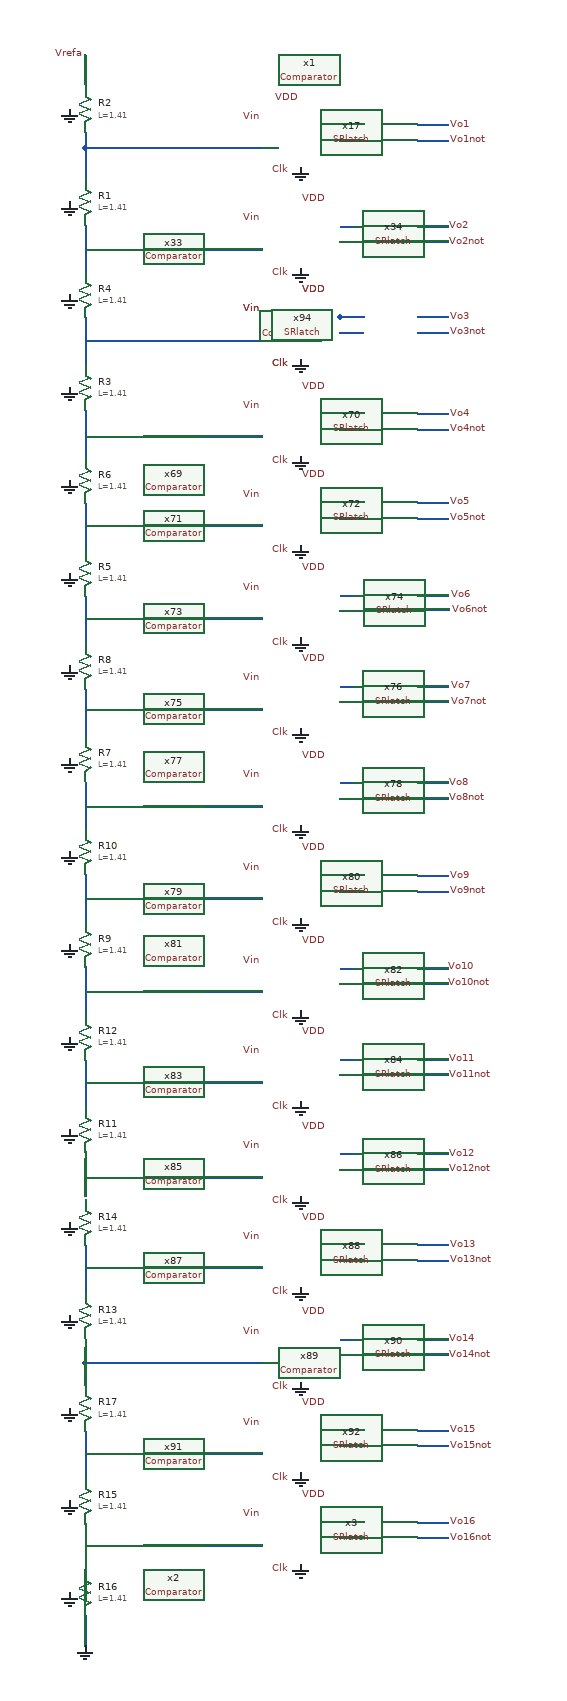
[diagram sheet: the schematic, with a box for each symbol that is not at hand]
v {xschem version=3.4.4 file_version=1.2
}
G {}
K {}
V {}
S {}
E {}
N -1900 -3260 -1670 -3260 {
lab=#net1}
N -1470 -3290 -1430 -3290 {
lab=Vo1}
N -1470 -3270 -1430 -3270 {
lab=Vo1not}
N -1900 -3280 -1900 -3260 {
lab=#net1}
N -1900 -3260 -1900 -3250 {
lab=#net1}
N -1900 -3250 -1900 -3220 {
lab=#net1}
N -1900 -3040 -1900 -3020 {
lab=#net2}
N -1900 -3020 -1900 -3010 {
lab=#net2}
N -1900 -3010 -1900 -2980 {
lab=#net2}
N -1900 -2800 -1900 -2780 {
lab=#net3}
N -1900 -2780 -1900 -2770 {
lab=#net3}
N -1900 -2770 -1900 -2740 {
lab=#net3}
N -1900 -2560 -1900 -2540 {
lab=#net4}
N -1900 -2540 -1900 -2530 {
lab=#net4}
N -1900 -2530 -1900 -2500 {
lab=#net4}
N -1900 -2320 -1900 -2300 {
lab=#net5}
N -1900 -2300 -1900 -2290 {
lab=#net5}
N -1900 -2290 -1900 -2260 {
lab=#net5}
N -1900 -2080 -1900 -2060 {
lab=#net6}
N -1900 -2060 -1900 -2050 {
lab=#net6}
N -1900 -2050 -1900 -2020 {
lab=#net6}
N -1900 -1840 -1900 -1820 {
lab=#net7}
N -1900 -1820 -1900 -1810 {
lab=#net7}
N -1900 -1810 -1900 -1780 {
lab=#net7}
N -1900 -1600 -1900 -1580 {
lab=#net8}
N -1900 -1580 -1900 -1570 {
lab=#net8}
N -1900 -1570 -1900 -1540 {
lab=#net8}
N -1900 -3160 -1900 -3100 {
lab=#net9}
N -1900 -2920 -1900 -2850 {
lab=#net10}
N -1900 -2680 -1900 -2620 {
lab=#net11}
N -1900 -3380 -1900 -3342.5 {
lab=#net12}
N -1570 -3290 -1552.5 -3290 {
lab=#net13}
N -1570 -3290 -1538.75 -3290 {
lab=#net13}
N -1571.25 -3270 -1540 -3270 {
lab=#net14}
N -1900 -3128.75 -1670 -3128.75 {
lab=#net9}
N -1470 -3158.75 -1430 -3158.75 {
lab=Vo2}
N -1470 -3138.75 -1430 -3138.75 {
lab=Vo2not}
N -1570 -3158.75 -1552.5 -3158.75 {
lab=#net15}
N -1570 -3158.75 -1538.75 -3158.75 {
lab=#net15}
N -1571.25 -3138.75 -1540 -3138.75 {
lab=#net16}
N -1900 -3011.25 -1670 -3011.25 {
lab=#net2}
N -1470 -3041.25 -1430 -3041.25 {
lab=Vo3}
N -1470 -3021.25 -1430 -3021.25 {
lab=Vo3not}
N -1570 -3041.25 -1552.5 -3041.25 {
lab=#net17}
N -1570 -3041.25 -1538.75 -3041.25 {
lab=#net17}
N -1571.25 -3021.25 -1540 -3021.25 {
lab=#net18}
N -1900 -2886.25 -1670 -2886.25 {
lab=#net10}
N -1470 -2916.25 -1430 -2916.25 {
lab=Vo4}
N -1470 -2896.25 -1430 -2896.25 {
lab=Vo4not}
N -1570 -2916.25 -1552.5 -2916.25 {
lab=#net19}
N -1570 -2916.25 -1538.75 -2916.25 {
lab=#net19}
N -1571.25 -2896.25 -1540 -2896.25 {
lab=#net20}
N -1900 -2771.25 -1670 -2771.25 {
lab=#net3}
N -1470 -2801.25 -1430 -2801.25 {
lab=Vo5}
N -1470 -2781.25 -1430 -2781.25 {
lab=Vo5not}
N -1570 -2801.25 -1552.5 -2801.25 {
lab=#net21}
N -1570 -2801.25 -1538.75 -2801.25 {
lab=#net21}
N -1571.25 -2781.25 -1540 -2781.25 {
lab=#net22}
N -1900 -2651.25 -1670 -2651.25 {
lab=#net11}
N -1470 -2681.25 -1430 -2681.25 {
lab=#net23}
N -1468.75 -2662.5 -1428.75 -2662.5 {
lab=#net24}
N -1570 -2681.25 -1552.5 -2681.25 {
lab=#net25}
N -1570 -2681.25 -1538.75 -2681.25 {
lab=#net25}
N -1571.25 -2661.25 -1540 -2661.25 {
lab=#net26}
N -1900 -2533.75 -1670 -2533.75 {
lab=#net4}
N -1470 -2563.75 -1430 -2563.75 {
lab=#net27}
N -1470 -2543.75 -1430 -2543.75 {
lab=#net28}
N -1570 -2563.75 -1552.5 -2563.75 {
lab=#net29}
N -1570 -2563.75 -1538.75 -2563.75 {
lab=#net29}
N -1571.25 -2543.75 -1540 -2543.75 {
lab=#net30}
N -1900 -2408.75 -1670 -2408.75 {
lab=#net31}
N -1470 -2438.75 -1430 -2438.75 {
lab=Vo8}
N -1470 -2418.75 -1430 -2418.75 {
lab=Vo8not}
N -1570 -2438.75 -1552.5 -2438.75 {
lab=#net32}
N -1570 -2438.75 -1538.75 -2438.75 {
lab=#net32}
N -1571.25 -2418.75 -1540 -2418.75 {
lab=#net33}
N -1900 -2288.75 -1670 -2288.75 {
lab=#net5}
N -1470 -2318.75 -1430 -2318.75 {
lab=Vo9}
N -1470 -2298.75 -1430 -2298.75 {
lab=Vo9not}
N -1570 -2318.75 -1552.5 -2318.75 {
lab=#net34}
N -1570 -2318.75 -1538.75 -2318.75 {
lab=#net34}
N -1571.25 -2298.75 -1540 -2298.75 {
lab=#net35}
N -1900 -2168.75 -1670 -2168.75 {
lab=#net36}
N -1470 -2198.75 -1430 -2198.75 {
lab=#net37}
N -1470 -2178.75 -1430 -2178.75 {
lab=#net38}
N -1570 -2198.75 -1552.5 -2198.75 {
lab=#net39}
N -1570 -2198.75 -1538.75 -2198.75 {
lab=#net39}
N -1571.25 -2178.75 -1540 -2178.75 {
lab=#net40}
N -1900 -2051.25 -1670 -2051.25 {
lab=#net6}
N -1470 -2081.25 -1430 -2081.25 {
lab=Vo11}
N -1470 -2061.25 -1430 -2061.25 {
lab=Vo11not}
N -1570 -2081.25 -1552.5 -2081.25 {
lab=#net41}
N -1570 -2081.25 -1538.75 -2081.25 {
lab=#net41}
N -1571.25 -2061.25 -1540 -2061.25 {
lab=#net42}
N -1900 -1928.75 -1670 -1928.75 {
lab=#net43}
N -1470 -1958.75 -1430 -1958.75 {
lab=Vo12}
N -1470 -1938.75 -1430 -1938.75 {
lab=Vo12not}
N -1570 -1958.75 -1552.5 -1958.75 {
lab=#net44}
N -1570 -1958.75 -1538.75 -1958.75 {
lab=#net44}
N -1571.25 -1938.75 -1540 -1938.75 {
lab=#net45}
N -1900 -1811.25 -1670 -1811.25 {
lab=#net7}
N -1470 -1841.25 -1430 -1841.25 {
lab=Vo13}
N -1470 -1821.25 -1430 -1821.25 {
lab=Vo13not}
N -1570 -1841.25 -1552.5 -1841.25 {
lab=#net46}
N -1570 -1841.25 -1538.75 -1841.25 {
lab=#net46}
N -1571.25 -1821.25 -1540 -1821.25 {
lab=#net47}
N -1900 -1688.75 -1670 -1688.75 {
lab=#net48}
N -1470 -1718.75 -1430 -1718.75 {
lab=Vo14}
N -1470 -1698.75 -1430 -1698.75 {
lab=Vo14not}
N -1570 -1718.75 -1552.5 -1718.75 {
lab=#net49}
N -1570 -1718.75 -1538.75 -1718.75 {
lab=#net49}
N -1571.25 -1698.75 -1540 -1698.75 {
lab=#net50}
N -1900 -1571.25 -1670 -1571.25 {
lab=#net8}
N -1470 -1601.25 -1430 -1601.25 {
lab=Vo15}
N -1470 -1581.25 -1430 -1581.25 {
lab=Vo15not}
N -1570 -1601.25 -1552.5 -1601.25 {
lab=#net51}
N -1570 -1601.25 -1538.75 -1601.25 {
lab=#net51}
N -1571.25 -1581.25 -1540 -1581.25 {
lab=#net52}
N -1900 -3011.25 -1670 -3011.25 {
lab=#net2}
N -1470 -3041.25 -1430 -3041.25 {
lab=Vo3}
N -1470 -3021.25 -1430 -3021.25 {
lab=Vo3not}
N -1570 -3041.25 -1552.5 -3041.25 {
lab=#net17}
N -1570 -3041.25 -1538.75 -3041.25 {
lab=#net17}
N -1571.25 -3021.25 -1540 -3021.25 {
lab=#net18}
N -1900 -1688.75 -1900 -1658.75 {
lab=#net48}
N -1900 -1718.75 -1900 -1688.75 {
lab=#net48}
N -1900 -1962.5 -1900 -1903.75 {
lab=#net43}
N -1900 -2201.25 -1900 -2140 {
lab=#net36}
N -1900 -2438.75 -1900 -2380 {
lab=#net31}
N -1900 -1481.25 -1900 -1461.25 {
lab=#net53}
N -1900 -1461.25 -1900 -1451.25 {
lab=#net53}
N -1900 -1451.25 -1900 -1421.25 {
lab=#net53}
N -1900 -1361.25 -1900 -1321.25 {
lab=GND}
N -1900 -1452.5 -1670 -1452.5 {
lab=#net53}
N -1470 -1482.5 -1430 -1482.5 {
lab=Vo16}
N -1470 -1462.5 -1430 -1462.5 {
lab=Vo16not}
N -1570 -1482.5 -1552.5 -1482.5 {
lab=#net54}
N -1570 -1482.5 -1538.75 -1482.5 {
lab=#net54}
N -1571.25 -1462.5 -1540 -1462.5 {
lab=#net55}
C {devices/lab_pin.sym} -1900 -3381.25 1 0 {name=p19 sig_type=std_logic lab=Vrefa}
C {devices/lab_pin.sym} -1671.25 -3300 0 0 {name=p57 lab=Vin
}
C {devices/lab_pin.sym} -1621.25 -3325 1 0 {name=p58 sig_type=std_logic lab=VDD}
C {devices/gnd.sym} -1621.25 -3235 0 0 {name=l17 lab=GND}
C {devices/lab_pin.sym} -1633.75 -3231.25 0 0 {name=p59 sig_type=std_logic lab=Clk}
C {devices/lab_pin.sym} -1430 -3290 2 0 {name=p86 sig_type=std_logic lab=Vo1}
C {devices/lab_pin.sym} -1430 -3270 2 0 {name=p91 sig_type=std_logic lab=Vo1not}
C {devices/lab_pin.sym} -1431.25 -3158.75 2 0 {name=p92 sig_type=std_logic lab=Vo2}
C {devices/lab_pin.sym} -1431.25 -3138.75 2 0 {name=p93 sig_type=std_logic lab=Vo2not}
C {devices/lab_pin.sym} -1430 -3041.25 2 0 {name=p94 sig_type=std_logic lab=Vo3}
C {devices/lab_pin.sym} -1430 -3021.25 2 0 {name=p95 sig_type=std_logic lab=Vo3not}
C {devices/lab_pin.sym} -1430 -2916.25 2 0 {name=p96 sig_type=std_logic lab=Vo4}
C {devices/lab_pin.sym} -1430 -2896.25 2 0 {name=p97 sig_type=std_logic lab=Vo4not}
C {devices/lab_pin.sym} -1430 -2801.25 2 0 {name=p98 sig_type=std_logic lab=Vo5}
C {devices/lab_pin.sym} -1430 -2781.25 2 0 {name=p99 sig_type=std_logic lab=Vo5not}
C {devices/lab_pin.sym} -1428.75 -2681.25 2 0 {name=p100 sig_type=std_logic lab=Vo6}
C {devices/lab_pin.sym} -1427.5 -2662.5 2 0 {name=p101 sig_type=std_logic lab=Vo6not}
C {devices/lab_pin.sym} -1428.75 -2563.75 2 0 {name=p102 sig_type=std_logic lab=Vo7}
C {devices/lab_pin.sym} -1428.75 -2543.75 2 0 {name=p103 sig_type=std_logic lab=Vo7not}
C {devices/lab_pin.sym} -1431.25 -2438.75 2 0 {name=p104 sig_type=std_logic lab=Vo8}
C {devices/lab_pin.sym} -1431.25 -2418.75 2 0 {name=p105 sig_type=std_logic lab=Vo8not}
C {devices/lab_pin.sym} -1430 -2318.75 2 0 {name=p106 sig_type=std_logic lab=Vo9}
C {devices/lab_pin.sym} -1430 -2298.75 2 0 {name=p107 sig_type=std_logic lab=Vo9not}
C {devices/lab_pin.sym} -1432.5 -2200 2 0 {name=p108 sig_type=std_logic lab=Vo10}
C {devices/lab_pin.sym} -1432.5 -2180 2 0 {name=p109 sig_type=std_logic lab=Vo10not}
C {devices/lab_pin.sym} -1431.25 -2081.25 2 0 {name=p110 sig_type=std_logic lab=Vo11}
C {devices/lab_pin.sym} -1431.25 -2061.25 2 0 {name=p111 sig_type=std_logic lab=Vo11not}
C {devices/lab_pin.sym} -1431.25 -1958.75 2 0 {name=p112 sig_type=std_logic lab=Vo12}
C {devices/lab_pin.sym} -1431.25 -1938.75 2 0 {name=p113 sig_type=std_logic lab=Vo12not}
C {devices/lab_pin.sym} -1430 -1841.25 2 0 {name=p114 sig_type=std_logic lab=Vo13}
C {devices/lab_pin.sym} -1430 -1821.25 2 0 {name=p115 sig_type=std_logic lab=Vo13not}
C {devices/lab_pin.sym} -1431.25 -1718.75 2 0 {name=p116 sig_type=std_logic lab=Vo14}
C {devices/lab_pin.sym} -1431.25 -1698.75 2 0 {name=p117 sig_type=std_logic lab=Vo14not}
C {devices/lab_pin.sym} -1430 -1601.25 2 0 {name=p118 sig_type=std_logic lab=Vo15}
C {devices/lab_pin.sym} -1430 -1581.25 2 0 {name=p119 sig_type=std_logic lab=Vo15not}
C {devices/lab_pin.sym} -1430 -1482.5 2 0 {name=p120 sig_type=std_logic lab=Vo16}
C {devices/lab_pin.sym} -1430 -1462.5 2 0 {name=p121 sig_type=std_logic lab=Vo16not}
C {xschem/Amplifiers/Comparator.sym} -1633.75 -3278.75 0 0 {name=x1}
C {xschem/StandardCells/SRlatch.sym} -1619.375 -3280 0 0 {name=x17}
C {devices/gnd.sym} -1920 -3310 1 0 {name=l18 lab=GND}
C {devices/gnd.sym} -1920 -3190 1 0 {name=l21 lab=GND}
C {dependencies/pdks/sky130B/libs.tech/xschem/sky130_fd_pr/res_high_po_1p41.sym} -1900 -3190 0 0 {name=R1
L=1.41
model=res_high_po_1p41
spiceprefix=X
mult=8}
C {dependencies/pdks/sky130B/libs.tech/xschem/sky130_fd_pr/res_high_po_1p41.sym} -1900 -3310 0 0 {name=R2
L=1.41
model=res_high_po_1p41
spiceprefix=X
mult=8}
C {devices/gnd.sym} -1920 -3070 1 0 {name=l22 lab=GND}
C {devices/gnd.sym} -1920 -2950 1 0 {name=l23 lab=GND}
C {dependencies/pdks/sky130B/libs.tech/xschem/sky130_fd_pr/res_high_po_1p41.sym} -1900 -2950 0 0 {name=R3
L=1.41
model=res_high_po_1p41
spiceprefix=X
mult=8}
C {dependencies/pdks/sky130B/libs.tech/xschem/sky130_fd_pr/res_high_po_1p41.sym} -1900 -3070 0 0 {name=R4
L=1.41
model=res_high_po_1p41
spiceprefix=X
mult=8}
C {devices/gnd.sym} -1920 -2830 1 0 {name=l24 lab=GND}
C {devices/gnd.sym} -1920 -2710 1 0 {name=l25 lab=GND}
C {dependencies/pdks/sky130B/libs.tech/xschem/sky130_fd_pr/res_high_po_1p41.sym} -1900 -2710 0 0 {name=R5
L=1.41
model=res_high_po_1p41
spiceprefix=X
mult=8}
C {dependencies/pdks/sky130B/libs.tech/xschem/sky130_fd_pr/res_high_po_1p41.sym} -1900 -2830 0 0 {name=R6
L=1.41
model=res_high_po_1p41
spiceprefix=X
mult=8}
C {devices/gnd.sym} -1920 -2590 1 0 {name=l26 lab=GND}
C {devices/gnd.sym} -1920 -2470 1 0 {name=l27 lab=GND}
C {dependencies/pdks/sky130B/libs.tech/xschem/sky130_fd_pr/res_high_po_1p41.sym} -1900 -2470 0 0 {name=R7
L=1.41
model=res_high_po_1p41
spiceprefix=X
mult=8}
C {dependencies/pdks/sky130B/libs.tech/xschem/sky130_fd_pr/res_high_po_1p41.sym} -1900 -2590 0 0 {name=R8
L=1.41
model=res_high_po_1p41
spiceprefix=X
mult=8}
C {devices/gnd.sym} -1920 -2350 1 0 {name=l28 lab=GND}
C {devices/gnd.sym} -1920 -2230 1 0 {name=l29 lab=GND}
C {dependencies/pdks/sky130B/libs.tech/xschem/sky130_fd_pr/res_high_po_1p41.sym} -1900 -2230 0 0 {name=R9
L=1.41
model=res_high_po_1p41
spiceprefix=X
mult=8}
C {dependencies/pdks/sky130B/libs.tech/xschem/sky130_fd_pr/res_high_po_1p41.sym} -1900 -2350 0 0 {name=R10
L=1.41
model=res_high_po_1p41
spiceprefix=X
mult=8}
C {devices/gnd.sym} -1920 -2110 1 0 {name=l30 lab=GND}
C {devices/gnd.sym} -1920 -1990 1 0 {name=l31 lab=GND}
C {dependencies/pdks/sky130B/libs.tech/xschem/sky130_fd_pr/res_high_po_1p41.sym} -1900 -1990 0 0 {name=R11
L=1.41
model=res_high_po_1p41
spiceprefix=X
mult=8}
C {dependencies/pdks/sky130B/libs.tech/xschem/sky130_fd_pr/res_high_po_1p41.sym} -1900 -2110 0 0 {name=R12
L=1.41
model=res_high_po_1p41
spiceprefix=X
mult=8}
C {devices/gnd.sym} -1920 -1870 1 0 {name=l32 lab=GND}
C {devices/gnd.sym} -1920 -1750 1 0 {name=l33 lab=GND}
C {dependencies/pdks/sky130B/libs.tech/xschem/sky130_fd_pr/res_high_po_1p41.sym} -1900 -1750 0 0 {name=R13
L=1.41
model=res_high_po_1p41
spiceprefix=X
mult=8}
C {dependencies/pdks/sky130B/libs.tech/xschem/sky130_fd_pr/res_high_po_1p41.sym} -1900 -1870 0 0 {name=R14
L=1.41
model=res_high_po_1p41
spiceprefix=X
mult=8}
C {devices/gnd.sym} -1920 -1630 1 0 {name=l34 lab=GND}
C {devices/gnd.sym} -1920 -1510 1 0 {name=l35 lab=GND}
C {dependencies/pdks/sky130B/libs.tech/xschem/sky130_fd_pr/res_high_po_1p41.sym} -1900 -1510 0 0 {name=R15
L=1.41
model=res_high_po_1p41
spiceprefix=X
mult=8}
C {dependencies/pdks/sky130B/libs.tech/xschem/sky130_fd_pr/res_high_po_1p41.sym} -1900 -1630 0 0 {name=R17
L=1.41
model=res_high_po_1p41
spiceprefix=X
mult=8}
C {devices/lab_pin.sym} -1671.25 -3168.75 0 0 {name=p1 lab=Vin
}
C {devices/lab_pin.sym} -1621.25 -3193.75 2 0 {name=p2 sig_type=std_logic lab=VDD}
C {devices/gnd.sym} -1621.25 -3103.75 0 0 {name=l19 lab=GND}
C {devices/lab_pin.sym} -1633.75 -3097.5 3 0 {name=p3 sig_type=std_logic lab=Clk}
C {xschem/Amplifiers/Comparator.sym} -1633.75 -3147.5 0 0 {name=x33}
C {xschem/StandardCells/SRlatch.sym} -1619.375 -3148.75 0 0 {name=x34}
C {devices/lab_pin.sym} -1671.25 -3051.25 0 0 {name=p20 lab=Vin
}
C {devices/lab_pin.sym} -1621.25 -3076.25 2 0 {name=p21 sig_type=std_logic lab=VDD}
C {devices/gnd.sym} -1621.25 -2986.25 0 0 {name=l20 lab=GND}
C {devices/lab_pin.sym} -1633.75 -2980 3 0 {name=p22 sig_type=std_logic lab=Clk}
C {xschem/Amplifiers/Comparator.sym} -1633.75 -3030 0 0 {name=x35}
C {xschem/StandardCells/SRlatch.sym} -1619.375 -3031.25 0 0 {name=x36}
C {devices/lab_pin.sym} -1671.25 -2926.25 0 0 {name=p225 lab=Vin
}
C {devices/lab_pin.sym} -1621.25 -2951.25 2 0 {name=p226 sig_type=std_logic lab=VDD}
C {devices/gnd.sym} -1621.25 -2861.25 0 0 {name=l70 lab=GND}
C {devices/lab_pin.sym} -1633.75 -2855 3 0 {name=p227 sig_type=std_logic lab=Clk}
C {xschem/Amplifiers/Comparator.sym} -1633.75 -2905 0 0 {name=x69}
C {xschem/StandardCells/SRlatch.sym} -1619.375 -2906.25 0 0 {name=x70}
C {devices/lab_pin.sym} -1671.25 -2811.25 0 0 {name=p230 lab=Vin
}
C {devices/lab_pin.sym} -1621.25 -2836.25 2 0 {name=p231 sig_type=std_logic lab=VDD}
C {devices/gnd.sym} -1621.25 -2746.25 0 0 {name=l71 lab=GND}
C {devices/lab_pin.sym} -1633.75 -2740 3 0 {name=p232 sig_type=std_logic lab=Clk}
C {xschem/Amplifiers/Comparator.sym} -1633.75 -2790 0 0 {name=x71}
C {xschem/StandardCells/SRlatch.sym} -1619.375 -2791.25 0 0 {name=x72}
C {devices/lab_pin.sym} -1671.25 -2691.25 0 0 {name=p235 lab=Vin
}
C {devices/lab_pin.sym} -1621.25 -2716.25 2 0 {name=p236 sig_type=std_logic lab=VDD}
C {devices/gnd.sym} -1621.25 -2626.25 0 0 {name=l72 lab=GND}
C {devices/lab_pin.sym} -1633.75 -2620 3 0 {name=p237 sig_type=std_logic lab=Clk}
C {xschem/Amplifiers/Comparator.sym} -1633.75 -2670 0 0 {name=x73}
C {xschem/StandardCells/SRlatch.sym} -1619.375 -2671.25 0 0 {name=x74}
C {devices/lab_pin.sym} -1671.25 -2573.75 0 0 {name=p240 lab=Vin
}
C {devices/lab_pin.sym} -1621.25 -2598.75 2 0 {name=p241 sig_type=std_logic lab=VDD}
C {devices/gnd.sym} -1621.25 -2508.75 0 0 {name=l73 lab=GND}
C {devices/lab_pin.sym} -1633.75 -2502.5 3 0 {name=p242 sig_type=std_logic lab=Clk}
C {xschem/Amplifiers/Comparator.sym} -1633.75 -2552.5 0 0 {name=x75}
C {xschem/StandardCells/SRlatch.sym} -1619.375 -2553.75 0 0 {name=x76}
C {devices/lab_pin.sym} -1671.25 -2448.75 0 0 {name=p245 lab=Vin
}
C {devices/lab_pin.sym} -1621.25 -2473.75 2 0 {name=p246 sig_type=std_logic lab=VDD}
C {devices/gnd.sym} -1621.25 -2383.75 0 0 {name=l74 lab=GND}
C {devices/lab_pin.sym} -1633.75 -2377.5 3 0 {name=p247 sig_type=std_logic lab=Clk}
C {xschem/Amplifiers/Comparator.sym} -1633.75 -2427.5 0 0 {name=x77}
C {xschem/StandardCells/SRlatch.sym} -1619.375 -2428.75 0 0 {name=x78}
C {devices/lab_pin.sym} -1671.25 -2328.75 0 0 {name=p250 lab=Vin
}
C {devices/lab_pin.sym} -1621.25 -2353.75 2 0 {name=p251 sig_type=std_logic lab=VDD}
C {devices/gnd.sym} -1621.25 -2263.75 0 0 {name=l75 lab=GND}
C {devices/lab_pin.sym} -1633.75 -2257.5 3 0 {name=p252 sig_type=std_logic lab=Clk}
C {xschem/Amplifiers/Comparator.sym} -1633.75 -2307.5 0 0 {name=x79}
C {xschem/StandardCells/SRlatch.sym} -1619.375 -2308.75 0 0 {name=x80}
C {devices/lab_pin.sym} -1671.25 -2208.75 0 0 {name=p255 lab=Vin
}
C {devices/lab_pin.sym} -1621.25 -2233.75 2 0 {name=p256 sig_type=std_logic lab=VDD}
C {devices/gnd.sym} -1621.25 -2143.75 0 0 {name=l76 lab=GND}
C {devices/lab_pin.sym} -1633.75 -2137.5 3 0 {name=p257 sig_type=std_logic lab=Clk}
C {xschem/Amplifiers/Comparator.sym} -1633.75 -2187.5 0 0 {name=x81}
C {xschem/StandardCells/SRlatch.sym} -1619.375 -2188.75 0 0 {name=x82}
C {devices/lab_pin.sym} -1671.25 -2091.25 0 0 {name=p260 lab=Vin
}
C {devices/lab_pin.sym} -1621.25 -2116.25 2 0 {name=p261 sig_type=std_logic lab=VDD}
C {devices/gnd.sym} -1621.25 -2026.25 0 0 {name=l77 lab=GND}
C {devices/lab_pin.sym} -1633.75 -2020 3 0 {name=p262 sig_type=std_logic lab=Clk}
C {xschem/Amplifiers/Comparator.sym} -1633.75 -2070 0 0 {name=x83}
C {xschem/StandardCells/SRlatch.sym} -1619.375 -2071.25 0 0 {name=x84}
C {devices/lab_pin.sym} -1671.25 -1968.75 0 0 {name=p265 lab=Vin
}
C {devices/lab_pin.sym} -1621.25 -1993.75 2 0 {name=p266 sig_type=std_logic lab=VDD}
C {devices/gnd.sym} -1621.25 -1903.75 0 0 {name=l78 lab=GND}
C {devices/lab_pin.sym} -1633.75 -1897.5 3 0 {name=p267 sig_type=std_logic lab=Clk}
C {xschem/Amplifiers/Comparator.sym} -1633.75 -1947.5 0 0 {name=x85}
C {xschem/StandardCells/SRlatch.sym} -1619.375 -1948.75 0 0 {name=x86}
C {devices/lab_pin.sym} -1671.25 -1851.25 0 0 {name=p270 lab=Vin
}
C {devices/lab_pin.sym} -1621.25 -1876.25 2 0 {name=p271 sig_type=std_logic lab=VDD}
C {devices/gnd.sym} -1621.25 -1786.25 0 0 {name=l79 lab=GND}
C {devices/lab_pin.sym} -1633.75 -1780 3 0 {name=p272 sig_type=std_logic lab=Clk}
C {xschem/Amplifiers/Comparator.sym} -1633.75 -1830 0 0 {name=x87}
C {xschem/StandardCells/SRlatch.sym} -1619.375 -1831.25 0 0 {name=x88}
C {devices/lab_pin.sym} -1671.25 -1728.75 0 0 {name=p275 lab=Vin
}
C {devices/lab_pin.sym} -1621.25 -1753.75 2 0 {name=p276 sig_type=std_logic lab=VDD}
C {devices/gnd.sym} -1621.25 -1663.75 0 0 {name=l80 lab=GND}
C {devices/lab_pin.sym} -1633.75 -1657.5 3 0 {name=p277 sig_type=std_logic lab=Clk}
C {xschem/Amplifiers/Comparator.sym} -1633.75 -1707.5 0 0 {name=x89}
C {xschem/StandardCells/SRlatch.sym} -1619.375 -1708.75 0 0 {name=x90}
C {devices/lab_pin.sym} -1671.25 -1611.25 0 0 {name=p280 lab=Vin
}
C {devices/lab_pin.sym} -1621.25 -1636.25 2 0 {name=p281 sig_type=std_logic lab=VDD}
C {devices/gnd.sym} -1621.25 -1546.25 0 0 {name=l81 lab=GND}
C {devices/lab_pin.sym} -1633.75 -1540 3 0 {name=p282 sig_type=std_logic lab=Clk}
C {xschem/Amplifiers/Comparator.sym} -1633.75 -1590 0 0 {name=x91}
C {xschem/StandardCells/SRlatch.sym} -1619.375 -1591.25 0 0 {name=x92}
C {devices/lab_pin.sym} -1671.25 -3051.25 0 0 {name=p285 lab=Vin
}
C {devices/lab_pin.sym} -1621.25 -3076.25 2 0 {name=p286 sig_type=std_logic lab=VDD}
C {devices/gnd.sym} -1621.25 -2986.25 0 0 {name=l82 lab=GND}
C {devices/lab_pin.sym} -1633.75 -2980 3 0 {name=p287 sig_type=std_logic lab=Clk}
C {xschem/Amplifiers/Comparator.sym} -1633.75 -3030 0 0 {name=x93}
C {xschem/StandardCells/SRlatch.sym} -1619.375 -3031.25 0 0 {name=x94}
C {devices/gnd.sym} -1920 -1391.25 1 0 {name=l2 lab=GND}
C {dependencies/pdks/sky130B/libs.tech/xschem/sky130_fd_pr/res_high_po_1p41.sym} -1900 -1391.25 0 0 {name=R16
L=1.41
model=res_high_po_1p41
spiceprefix=X
mult=8}
C {devices/lab_pin.sym} -1671.25 -1492.5 0 0 {name=p7 lab=Vin
}
C {devices/lab_pin.sym} -1621.25 -1517.5 2 0 {name=p8 sig_type=std_logic lab=VDD}
C {devices/gnd.sym} -1621.25 -1427.5 0 0 {name=l4 lab=GND}
C {devices/lab_pin.sym} -1633.75 -1421.25 3 0 {name=p9 sig_type=std_logic lab=Clk}
C {xschem/Amplifiers/Comparator.sym} -1633.75 -1471.25 0 0 {name=x2}
C {xschem/StandardCells/SRlatch.sym} -1619.375 -1472.5 0 0 {name=x3}
C {devices/gnd.sym} -1900 -1322.5 0 0 {name=l1 lab=GND}
